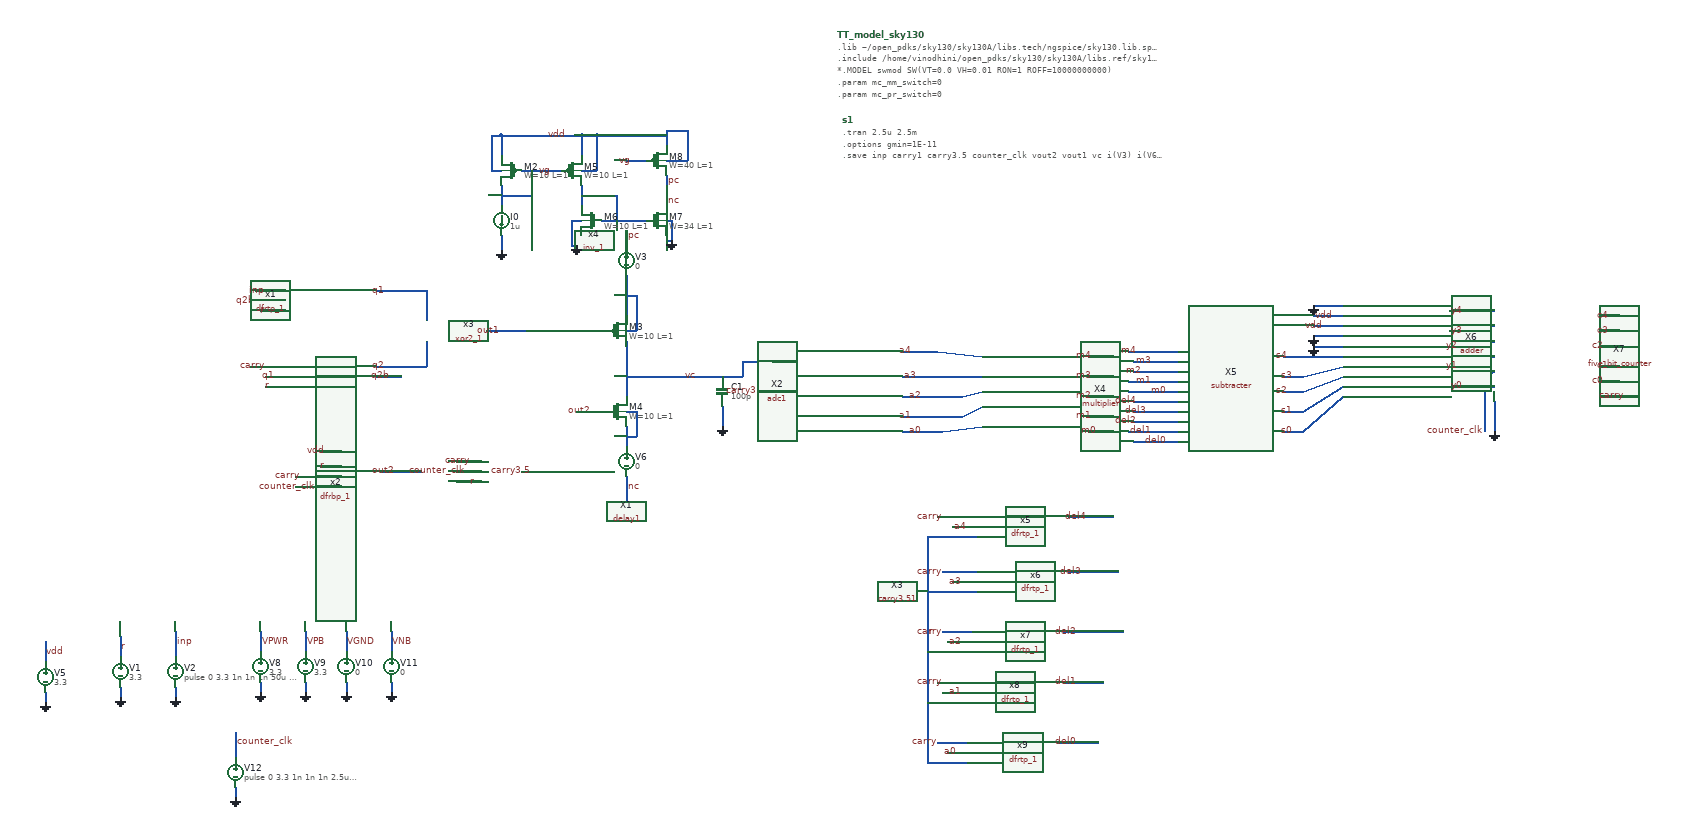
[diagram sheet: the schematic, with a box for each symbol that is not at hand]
v {xschem version=3.0.0 file_version=1.2 }
G {}
K {}
V {}
S {}
E {}
N -800 150 -800 170 { lab=GND}
N -800 40 -800 90 { lab=inp}
N -910 150 -910 170 { lab=GND}
N -910 50 -910 90 { lab=r}
N -1060 160 -1060 180 { lab=GND}
N -1060 60 -1060 100 { lab=vdd}
N 100 -370 100 -330 { lab=#net1}
N 100 -490 100 -430 { lab=vc}
N 100 -470 290 -470 { lab=vc}
N 100 -670 100 -600 { lab=#net2}
N 290 -410 290 -370 { lab=GND}
N 100 -540 100 -490 { lab=vc}
N 0 -560 10 -560 { lab=#net3}
N 50 -560 60 -560 { lab=#net3}
N 100 -610 100 -590 { lab=#net2}
N 0 -400 60 -400 { lab=out2}
N 100 -400 120 -400 { lab=#net1}
N 120 -400 120 -350 { lab=#net1}
N 100 -350 120 -350 { lab=#net1}
N 100 -560 120 -560 { lab=#net2}
N 120 -630 120 -560 { lab=#net2}
N 100 -630 120 -630 { lab=#net2}
N 360 -440 440 -440 { lab=carry3.5}
N 650 -360 730 -360 { lab=a0}
N 650 -390 720 -390 { lab=a1}
N 650 -430 720 -430 { lab=a2}
N 650 -470 730 -470 { lab=a3}
N 390 -500 440 -500 { lab=vc}
N 650 -520 720 -520 { lab=a4}
N 100 -760 100 -730 { lab=pc}
N 100 -270 100 -220 { lab=nc}
N -400 -470 -350 -470 { lab=q2b}
N -640 -620 -580 -620 { lab=q2b}
N -400 -490 -350 -490 { lab=q2}
N -400 -640 -350 -640 { lab=q1}
N -620 -450 -580 -450 { lab=r}
N -630 -600 -580 -600 { lab=r}
N -650 -490 -580 -490 { lab=carry}
N -640 -640 -580 -640 { lab=inp}
N -620 -470 -580 -470 { lab=q1}
N -350 -640 -310 -640 { lab=q1}
N -310 -640 -300 -640 { lab=q1}
N -300 -640 -300 -580 { lab=q1}
N -350 -490 -310 -490 { lab=q2}
N -310 -490 -300 -490 { lab=q2}
N -300 -540 -300 -490 { lab=q2}
N -180 -560 -100 -560 { lab=out1}
N -20 -560 10 -560 { lab=#net3}
N -0 -560 50 -560 { lab=#net3}
N 290 -470 330 -470 { lab=vc}
N -630 140 -630 160 { lab=GND}
N -630 40 -630 80 { lab=VPWR}
N -540 140 -540 160 { lab=GND}
N -540 40 -540 80 { lab=VPB}
N -460 140 -460 160 { lab=GND}
N -460 40 -460 80 { lab=VGND}
N -370 140 -370 160 { lab=GND}
N -370 40 -370 80 { lab=VNB}
N -560 -250 -470 -250 { lab=counter_clk}
N -560 -270 -470 -270 { lab=carry}
N -510 -290 -470 -290 { lab=r}
N -510 -320 -470 -320 { lab=vdd}
N -680 350 -680 370 { lab=GND}
N -680 240 -680 290 { lab=counter_clk}
N -390 -280 -310 -280 { lab=out2}
N -150 -950 -150 -910 { lab=vdd}
N -170 -880 -150 -880 { lab=vdd}
N -170 -950 -170 -880 { lab=vdd}
N -170 -950 -150 -950 { lab=vdd}
N -150 -850 -150 -810 { lab=vg}
N -150 -750 -150 -720 { lab=GND}
N -110 -880 -30 -880 { lab=vg}
N -150 -830 -90 -830 { lab=vg}
N -90 -880 -90 -830 { lab=vg}
N 10 -880 40 -880 { lab=vdd}
N 40 -950 40 -880 { lab=vdd}
N 10 -950 40 -950 { lab=vdd}
N 10 -950 10 -910 { lab=vdd}
N -150 -950 10 -950 { lab=vdd}
N 10 -850 10 -810 { lab=#net4}
N -10 -780 10 -780 { lab=GND}
N -10 -780 -10 -730 { lab=GND}
N -10 -730 10 -730 { lab=GND}
N 10 -750 10 -730 { lab=GND}
N 50 -780 140 -780 { lab=#net4}
N 180 -780 190 -780 { lab=GND}
N 190 -780 190 -740 { lab=GND}
N 180 -740 190 -740 { lab=GND}
N 180 -750 180 -740 { lab=GND}
N 10 -830 80 -830 { lab=#net4}
N 80 -830 80 -780 { lab=#net4}
N 180 -900 220 -900 { lab=vdd}
N 220 -960 220 -900 { lab=vdd}
N 180 -960 220 -960 { lab=vdd}
N 180 -960 180 -930 { lab=vdd}
N 40 -950 180 -950 { lab=vdd}
N 100 -900 140 -900 { lab=vg}
N 180 -870 180 -850 { lab=pc}
N 180 -830 180 -810 { lab=nc}
N -240 -300 -190 -300 { lab=carry}
N -240 -280 -190 -280 { lab=counter_clk}
N -240 -260 -190 -260 { lab=r}
N -110 -280 -60 -280 { lab=carry3.5}
N 720 -520 810 -510 { lab=a4}
N 730 -470 810 -470 { lab=a3}
N 720 -430 740 -430 { lab=a2}
N 740 -430 750 -430 { lab=a2}
N 750 -430 760 -430 { lab=a2}
N 760 -430 770 -430 { lab=a2}
N 770 -430 810 -440 { lab=a2}
N 720 -390 770 -390 { lab=a1}
N 770 -390 810 -410 { lab=a1}
N 730 -360 810 -370 { lab=a0}
N 720 -190 800 -190 { lab=carry}
N 750 -170 800 -170 { lab=a4}
N 700 -150 800 -150 { lab=r}
N 700 -150 700 300 { lab=r}
N 700 300 780 300 { lab=r}
N 700 180 790 180 { lab=r}
N 700 80 790 80 { lab=r}
N 700 -40 800 -40 { lab=r}
N 730 -80 800 -80 { lab=carry}
N 750 -60 800 -60 { lab=a3}
N 730 40 790 40 { lab=carry}
N 740 60 790 60 { lab=a2}
N 720 140 790 140 { lab=carry}
N 730 160 790 160 { lab=a1}
N 720 260 780 260 { lab=carry}
N 740 280 780 280 { lab=a0}
N 980 -190 1070 -190 { lab=del4}
N 980 -80 1080 -80 { lab=del3}
N 970 40 1090 40 { lab=del2}
N 970 140 1050 140 { lab=del1}
N 960 260 1040 260 { lab=del0}
N 1020 -360 1070 -360 { lab=m0}
N 1020 -390 1070 -390 { lab=m1}
N 1020 -430 1070 -430 { lab=m2}
N 1020 -470 1070 -470 { lab=m3}
N 1020 -510 1070 -510 { lab=m4}
N 1110 -340 1200 -340 { lab=del0}
N 1100 -360 1200 -360 { lab=del1}
N 1110 -380 1200 -380 { lab=del2}
N 1110 -400 1200 -400 { lab=del3}
N 1110 -420 1200 -420 { lab=del4}
N 1100 -440 1200 -440 { lab=m0}
N 1100 -460 1200 -460 { lab=m1}
N 1110 -480 1200 -480 { lab=m2}
N 1110 -500 1200 -500 { lab=m3}
N 1100 -520 1200 -520 { lab=m4}
N 1410 -360 1450 -360 { lab=s0}
N 1410 -400 1450 -400 { lab=s1}
N 1410 -440 1450 -440 { lab=s2}
N 1410 -470 1450 -470 { lab=s3}
N 1410 -510 1450 -510 { lab=s4}
N 1450 -510 1530 -510 { lab=s4}
N 1450 -470 1530 -490 { lab=s3}
N 1450 -440 1530 -470 { lab=s2}
N 1450 -400 1530 -450 { lab=s1}
N 1450 -360 1530 -430 { lab=s0}
N 1470 -610 1530 -610 { lab=GND}
N 1470 -590 1530 -590 { lab=vdd}
N 1470 -570 1530 -570 { lab=vdd}
N 1470 -550 1530 -550 { lab=GND}
N 1470 -530 1530 -530 { lab=GND}
N 1740 -450 1780 -450 { lab=y0}
N 1740 -490 1780 -490 { lab=y1}
N 1740 -530 1780 -530 { lab=y2}
N 1740 -560 1780 -560 { lab=y3}
N 1740 -600 1780 -600 { lab=y4}
N 1780 -600 1830 -600 { lab=y4}
N 1780 -560 1830 -570 { lab=y3}
N 1780 -530 1830 -540 { lab=y2}
N 1780 -490 1830 -510 { lab=y1}
N 1780 -450 1830 -480 { lab=y0}
N 1810 -450 1830 -450 { lab=counter_clk}
N 1810 -450 1810 -360 { lab=counter_clk}
N 1830 -420 1830 -360 { lab=GND}
N 2040 -430 2120 -430 { lab=carry}
N 2040 -460 2080 -460 { lab=c0}
N 2040 -490 2080 -490 { lab=c1}
N 2040 -530 2070 -530 { lab=c2}
N 2070 -530 2080 -530 { lab=c2}
N 2040 -560 2080 -560 { lab=c3}
N 2040 -590 2080 -590 { lab=c4}
N 330 -500 330 -470 { lab=vc}
N 330 -500 400 -500 { lab=vc}
C {devices/code.sym} 520 -1150 0 0 {name=TT_model_sky130
format=@value
only_toplevel=true
value="
.lib ~/open_pdks/sky130/sky130A/libs.tech/ngspice/sky130.lib.spice tt
.include /home/vinodhini/open_pdks/sky130/sky130A/libs.ref/sky130_fd_sc_hvl/spice/sky130_fd_sc_hvl.spice

*.MODEL swmod SW(VT=0.0 VH=0.01 RON=1 ROFF=10000000000)
.param mc_mm_switch=0
.param mc_pr_switch=0"

.include ~/open_pdks/sky130/sky130A/libs.tech/ngspice/corners/tt/nonfet.spice


*model
*.include ~/open_pdks/sky130/sky130A/libs.tech/ngspice/all.spice


 
*mosfet
*.include ~/open_pdks/sky130/sky130A/libs.ref/sky130_fd_pr/spice/sky130_fd_pr__pfet_g5v0d10v5__tt.corner.spice
*.inclued ~/open_pdks/sky130/sky130A/libs.ref/sky130_fd_pr/spice/sky130_fd_pr__nfet_g5v0d10v5__tt.corner.spice
*mismatch parameters
*.include ~/open_pdks/sky130/sky130A/libs.ref/sky130_fd_pr/spice/sky130_fd_pr__pfet_g5v0d10v5__mismatch.corner.spice
*.include ~/open_pdks/sky130/sky130A/libs.ref/sky130_fd_pr/spice/sky130_fd_pr__nfet_g5v0d10v5__mismatch.corner.spice
}
C {devices/code_shown.sym} 530 -980 0 0 {name=s1 only_toplevel=false value="
.tran 2.5u 2.5m
.options gmin=1E-11
.save inp carry1 carry3.5 counter_clk vout2 vout1 vc i(V3) i(V6) a0 a1 a2 a3 a4 m0 m1 m2 m3 m4 del0 del1 del2 del3 del4 s0 s1 s2 s3 s4"}
C {devices/vsource.sym} -800 120 0 0 {name=V2 value="pulse 0 3.3 1n 1n 1n 50u 100u"}
C {devices/gnd.sym} -800 170 0 0 {name=l22 lab=GND}
C {devices/lab_pin.sym} -800 60 2 0 {name=l25 sig_type=std_logic lab=inp}
C {devices/vsource.sym} -910 120 0 0 {name=V1 value=3.3}
C {devices/gnd.sym} -910 170 0 0 {name=l4 lab=GND}
C {devices/lab_pin.sym} -910 70 2 0 {name=l5 sig_type=std_logic lab=r}
C {devices/vsource.sym} -1060 130 0 0 {name=V5 value=3.3}
C {devices/gnd.sym} -1060 180 0 0 {name=l26 lab=GND}
C {devices/lab_pin.sym} -1060 80 2 0 {name=l27 sig_type=std_logic lab=vdd}
C {devices/gnd.sym} 290 -370 0 0 {name=l32 lab=GND}
C {devices/capa.sym} 290 -440 0 0 {name=C1
m=1
value=100p
footprint=1206
device="ceramic capacitor"}
C {devices/lab_pin.sym} 240 -470 1 0 {name=l33 sig_type=std_logic lab=vc}
C {sky130_fd_pr/pfet_g5v0d10v5.sym} 80 -560 0 0 {name=M3
L=1
W=10
nf=1
mult=1
ad="'int((nf+1)/2) * W/nf * 0.29'" 
pd="'2*int((nf+1)/2) * (W/nf + 0.29)'"
as="'int((nf+2)/2) * W/nf * 0.29'" 
ps="'2*int((nf+2)/2) * (W/nf + 0.29)'"
nrd="'0.29 / W'" nrs="'0.29 / W'"
sa=0 sb=0 sd=0
model=pfet_g5v0d10v5
spiceprefix=X
}
C {sky130_fd_pr/nfet_g5v0d10v5.sym} 80 -400 0 0 {name=M4
L=1
W=10
nf=1
mult=1
ad="'int((nf+1)/2) * W/nf * 0.29'" 
pd="'2*int((nf+1)/2) * (W/nf + 0.29)'"
as="'int((nf+2)/2) * W/nf * 0.29'" 
ps="'2*int((nf+2)/2) * (W/nf + 0.29)'"
nrd="'0.29 / W'" nrs="'0.29 / W'"
sa=0 sb=0 sd=0
model=nfet_g5v0d10v5
spiceprefix=X
}
C {devices/lab_pin.sym} 30 -400 1 0 {name=l30 sig_type=std_logic lab=out2}
C {devices/lab_pin.sym} 380 -440 3 0 {name=l36 sig_type=std_logic lab=carry3.5}
C {devices/lab_pin.sym} 690 -360 3 0 {name=l37 sig_type=std_logic lab=a0}
C {devices/lab_pin.sym} 670 -390 3 0 {name=l38 sig_type=std_logic lab=a1}
C {devices/lab_pin.sym} 690 -430 3 0 {name=l39 sig_type=std_logic lab=a2}
C {devices/lab_pin.sym} 680 -470 3 0 {name=l40 sig_type=std_logic lab=a3}
C {devices/lab_pin.sym} 670 -520 3 0 {name=l64 sig_type=std_logic lab=a4}
C {devices/vsource.sym} 100 -700 0 0 {name=V3 value=0}
C {devices/vsource.sym} 100 -300 0 0 {name=V6 value=0}
C {sky130_stdcells/dfrbp_1.sym} -490 -470 0 0 {name=x2 VGND=VGND VNB=VNB VPB=VPB VPWR=VPWR prefix=sky130_fd_sc_hvl__ }
C {devices/lab_pin.sym} -370 -470 3 0 {name=l35 sig_type=std_logic lab=q2b}
C {devices/lab_pin.sym} -640 -620 0 0 {name=l97 sig_type=std_logic lab=q2b}
C {devices/lab_pin.sym} -380 -490 1 0 {name=l98 sig_type=std_logic lab=q2}
C {sky130_stdcells/dfrtp_1.sym} -490 -620 0 0 {name=x1 VGND=VGND VNB=VNB VPB=VPB VPWR=VPWR prefix=sky130_fd_sc_hvl__ }
C {devices/lab_pin.sym} -380 -640 1 0 {name=l99 sig_type=std_logic lab=q1}
C {devices/lab_pin.sym} -610 -450 1 0 {name=l100 sig_type=std_logic lab=r}
C {devices/lab_pin.sym} -620 -600 1 0 {name=l101 sig_type=std_logic lab=r}
C {devices/lab_pin.sym} -620 -490 1 0 {name=l102 sig_type=std_logic lab=carry}
C {devices/lab_pin.sym} -620 -640 1 0 {name=l103 sig_type=std_logic lab=inp}
C {devices/lab_pin.sym} -600 -470 1 0 {name=l104 sig_type=std_logic lab=q1}
C {sky130_stdcells/xor2_1.sym} -240 -560 0 0 {name=x3 VGND=VGND VNB=VNB VPB=VPB VPWR=VPWR prefix=sky130_fd_sc_hvl__ }
C {devices/lab_pin.sym} -150 -560 1 0 {name=l1 sig_type=std_logic lab=out1}
C {sky130_stdcells/inv_1.sym} -60 -560 0 0 {name=x4 VGND=VGND VNB=VNB VPB=VPB VPWR=VPWR prefix=sky130_fd_sc_hvl__ }
C {devices/vsource.sym} -630 110 0 0 {name=V8 value=3.3}
C {devices/gnd.sym} -630 160 0 0 {name=l6 lab=GND}
C {devices/lab_pin.sym} -630 60 2 0 {name=l7 sig_type=std_logic lab=VPWR}
C {devices/vsource.sym} -540 110 0 0 {name=V9 value=3.3}
C {devices/gnd.sym} -540 160 0 0 {name=l8 lab=GND}
C {devices/lab_pin.sym} -540 60 2 0 {name=l9 sig_type=std_logic lab=VPB}
C {devices/vsource.sym} -460 110 0 0 {name=V10 value=0}
C {devices/gnd.sym} -460 160 0 0 {name=l10 lab=GND}
C {devices/lab_pin.sym} -460 60 2 0 {name=l11 sig_type=std_logic lab=VGND}
C {devices/vsource.sym} -370 110 0 0 {name=V11 value=0}
C {devices/gnd.sym} -370 160 0 0 {name=l12 lab=GND}
C {devices/lab_pin.sym} -370 60 2 0 {name=l13 sig_type=std_logic lab=VNB}
C {/home/vinodhini/Documents/delay1.sym} 270 -20 0 0 {name=X1}
C {devices/lab_pin.sym} -550 -270 1 0 {name=l14 sig_type=std_logic lab=carry}
C {devices/lab_pin.sym} -500 -290 1 0 {name=l15 sig_type=std_logic lab=r}
C {devices/lab_pin.sym} -500 -320 1 0 {name=l16 sig_type=std_logic lab=vdd}
C {devices/lab_pin.sym} -520 -250 3 0 {name=l19 sig_type=std_logic lab=counter_clk}
C {devices/vsource.sym} -680 320 0 0 {name=V12 value="pulse 0 3.3 1n 1n 1n 2.5u 5u"}
C {devices/gnd.sym} -680 370 0 0 {name=l20 lab=GND}
C {devices/lab_pin.sym} -680 260 2 0 {name=l23 sig_type=std_logic lab=counter_clk}
C {devices/lab_pin.sym} -360 -280 1 0 {name=l24 sig_type=std_logic lab=out2}
C {sky130_fd_pr/pfet_g5v0d10v5.sym} -130 -880 0 1 {name=M2
L=1
W=10
nf=1
mult=1
ad="'int((nf+1)/2) * W/nf * 0.29'" 
pd="'2*int((nf+1)/2) * (W/nf + 0.29)'"
as="'int((nf+2)/2) * W/nf * 0.29'" 
ps="'2*int((nf+2)/2) * (W/nf + 0.29)'"
nrd="'0.29 / W'" nrs="'0.29 / W'"
sa=0 sb=0 sd=0
model=pfet_g5v0d10v5
spiceprefix=X
}
C {devices/isource.sym} -150 -780 0 0 {name=I0 value=1u}
C {devices/gnd.sym} -150 -720 0 0 {name=l21 lab=GND}
C {sky130_fd_pr/pfet_g5v0d10v5.sym} -10 -880 0 0 {name=M5
L=1
W=10
nf=1
mult=1
ad="'int((nf+1)/2) * W/nf * 0.29'" 
pd="'2*int((nf+1)/2) * (W/nf + 0.29)'"
as="'int((nf+2)/2) * W/nf * 0.29'" 
ps="'2*int((nf+2)/2) * (W/nf + 0.29)'"
nrd="'0.29 / W'" nrs="'0.29 / W'"
sa=0 sb=0 sd=0
model=pfet_g5v0d10v5
spiceprefix=X
}
C {sky130_fd_pr/nfet_g5v0d10v5.sym} 30 -780 0 1 {name=M6
L=1
W=10
nf=1
mult=1
ad="'int((nf+1)/2) * W/nf * 0.29'" 
pd="'2*int((nf+1)/2) * (W/nf + 0.29)'"
as="'int((nf+2)/2) * W/nf * 0.29'" 
ps="'2*int((nf+2)/2) * (W/nf + 0.29)'"
nrd="'0.29 / W'" nrs="'0.29 / W'"
sa=0 sb=0 sd=0
model=nfet_g5v0d10v5
spiceprefix=X
}
C {devices/gnd.sym} 0 -730 0 0 {name=l31 lab=GND}
C {sky130_fd_pr/nfet_g5v0d10v5.sym} 160 -780 0 0 {name=M7
L=1
W=34
nf=1
mult=1
ad="'int((nf+1)/2) * W/nf * 0.29'" 
pd="'2*int((nf+1)/2) * (W/nf + 0.29)'"
as="'int((nf+2)/2) * W/nf * 0.29'" 
ps="'2*int((nf+2)/2) * (W/nf + 0.29)'"
nrd="'0.29 / W'" nrs="'0.29 / W'"
sa=0 sb=0 sd=0
model=nfet_g5v0d10v5
spiceprefix=X
}
C {devices/gnd.sym} 190 -740 0 0 {name=l34 lab=GND}
C {sky130_fd_pr/pfet_g5v0d10v5.sym} 160 -900 0 0 {name=M8
L=1
W=40
nf=1
mult=1
ad="'int((nf+1)/2) * W/nf * 0.29'" 
pd="'2*int((nf+1)/2) * (W/nf + 0.29)'"
as="'int((nf+2)/2) * W/nf * 0.29'" 
ps="'2*int((nf+2)/2) * (W/nf + 0.29)'"
nrd="'0.29 / W'" nrs="'0.29 / W'"
sa=0 sb=0 sd=0
model=pfet_g5v0d10v5
spiceprefix=X
}
C {devices/lab_pin.sym} -50 -880 1 0 {name=l42 sig_type=std_logic lab=vg}
C {devices/lab_pin.sym} 110 -900 1 0 {name=l43 sig_type=std_logic lab=vg}
C {devices/lab_pin.sym} 180 -860 2 0 {name=l28 sig_type=std_logic lab=pc}
C {devices/lab_pin.sym} 180 -820 2 0 {name=l29 sig_type=std_logic lab=nc}
C {devices/lab_pin.sym} 100 -750 2 0 {name=l44 sig_type=std_logic lab=pc}
C {devices/lab_pin.sym} 100 -250 2 0 {name=l45 sig_type=std_logic lab=nc}
C {devices/lab_pin.sym} -20 -950 1 0 {name=l46 sig_type=std_logic lab=vdd}
C {/home/vinodhini/Documents/adc1.sym} 600 -390 0 0 {name=X2}
C {/home/vinodhini/Documents/carry3.51.sym} 550 -30 0 0 {name=X3}
C {devices/lab_pin.sym} -200 -260 3 0 {name=l41 sig_type=std_logic lab=r}
C {devices/lab_pin.sym} -220 -280 3 0 {name=l47 sig_type=std_logic lab=counter_clk}
C {devices/lab_pin.sym} -210 -300 1 0 {name=l48 sig_type=std_logic lab=carry}
C {devices/lab_pin.sym} -90 -280 1 0 {name=l49 sig_type=std_logic lab=carry3.5}
C {/home/vinodhini/Documents/multiplier.sym} 970 -390 0 0 {name=X4}
C {sky130_stdcells/dfrtp_1.sym} 890 -170 0 0 {name=x5 VGND=VGND VNB=VNB VPB=VPB VPWR=VPWR prefix=sky130_fd_sc_hvl__ }
C {sky130_stdcells/dfrtp_1.sym} 890 -60 0 0 {name=x6 VGND=VGND VNB=VNB VPB=VPB VPWR=VPWR prefix=sky130_fd_sc_hvl__ }
C {sky130_stdcells/dfrtp_1.sym} 880 60 0 0 {name=x7 VGND=VGND VNB=VNB VPB=VPB VPWR=VPWR prefix=sky130_fd_sc_hvl__ }
C {sky130_stdcells/dfrtp_1.sym} 880 160 0 0 {name=x8 VGND=VGND VNB=VNB VPB=VPB VPWR=VPWR prefix=sky130_fd_sc_hvl__ }
C {sky130_stdcells/dfrtp_1.sym} 870 280 0 0 {name=x9 VGND=VGND VNB=VNB VPB=VPB VPWR=VPWR prefix=sky130_fd_sc_hvl__ }
C {devices/lab_pin.sym} 700 40 2 0 {name=l2 sig_type=std_logic lab=r}
C {devices/lab_pin.sym} 730 -190 1 0 {name=l3 sig_type=std_logic lab=carry}
C {devices/lab_pin.sym} 730 -80 1 0 {name=l50 sig_type=std_logic lab=carry}
C {devices/lab_pin.sym} 730 40 1 0 {name=l51 sig_type=std_logic lab=carry}
C {devices/lab_pin.sym} 730 140 1 0 {name=l52 sig_type=std_logic lab=carry}
C {devices/lab_pin.sym} 720 260 1 0 {name=l53 sig_type=std_logic lab=carry}
C {devices/lab_pin.sym} 760 280 1 0 {name=l54 sig_type=std_logic lab=a0}
C {devices/lab_pin.sym} 770 160 1 0 {name=l55 sig_type=std_logic lab=a1}
C {devices/lab_pin.sym} 770 60 1 0 {name=l56 sig_type=std_logic lab=a2}
C {devices/lab_pin.sym} 770 -60 1 0 {name=l57 sig_type=std_logic lab=a3}
C {devices/lab_pin.sym} 780 -170 1 0 {name=l58 sig_type=std_logic lab=a4}
C {devices/lab_pin.sym} 1000 260 1 0 {name=l59 sig_type=std_logic lab=del0}
C {devices/lab_pin.sym} 1000 140 1 0 {name=l60 sig_type=std_logic lab=del1}
C {devices/lab_pin.sym} 1000 40 1 0 {name=l61 sig_type=std_logic lab=del2}
C {devices/lab_pin.sym} 1010 -80 1 0 {name=l62 sig_type=std_logic lab=del3}
C {devices/lab_pin.sym} 1020 -190 1 0 {name=l63 sig_type=std_logic lab=del4}
C {/home/vinodhini/Documents/subtracter.sym} 1360 -370 0 0 {name=X5}
C {devices/lab_pin.sym} 1040 -360 3 0 {name=l65 sig_type=std_logic lab=m0}
C {devices/lab_pin.sym} 1030 -390 3 0 {name=l66 sig_type=std_logic lab=m1}
C {devices/lab_pin.sym} 1030 -430 3 0 {name=l67 sig_type=std_logic lab=m2}
C {devices/lab_pin.sym} 1030 -470 3 0 {name=l68 sig_type=std_logic lab=m3}
C {devices/lab_pin.sym} 1030 -510 3 0 {name=l69 sig_type=std_logic lab=m4}
C {devices/lab_pin.sym} 1180 -440 3 0 {name=l70 sig_type=std_logic lab=m0}
C {devices/lab_pin.sym} 1150 -460 3 0 {name=l71 sig_type=std_logic lab=m1}
C {devices/lab_pin.sym} 1130 -480 3 0 {name=l72 sig_type=std_logic lab=m2}
C {devices/lab_pin.sym} 1150 -500 3 0 {name=l73 sig_type=std_logic lab=m3}
C {devices/lab_pin.sym} 1120 -520 3 0 {name=l74 sig_type=std_logic lab=m4}
C {devices/lab_pin.sym} 1120 -420 1 0 {name=l75 sig_type=std_logic lab=del4}
C {devices/lab_pin.sym} 1140 -400 1 0 {name=l76 sig_type=std_logic lab=del3}
C {devices/lab_pin.sym} 1120 -380 3 0 {name=l77 sig_type=std_logic lab=del2}
C {devices/lab_pin.sym} 1150 -360 3 0 {name=l78 sig_type=std_logic lab=del1}
C {devices/lab_pin.sym} 1180 -340 3 0 {name=l79 sig_type=std_logic lab=del0}
C {devices/lab_pin.sym} 1430 -360 3 0 {name=l80 sig_type=std_logic lab=s0}
C {devices/lab_pin.sym} 1430 -400 3 0 {name=l81 sig_type=std_logic lab=s1}
C {devices/lab_pin.sym} 1420 -440 3 0 {name=l82 sig_type=std_logic lab=s2}
C {devices/lab_pin.sym} 1430 -470 3 0 {name=l83 sig_type=std_logic lab=s3}
C {devices/lab_pin.sym} 1420 -510 3 0 {name=l84 sig_type=std_logic lab=s4}
C {/home/vinodhini/Documents/adder.sym} 1690 -460 0 0 {name=X6}
C {devices/gnd.sym} 1470 -530 0 0 {name=l85 lab=GND}
C {devices/gnd.sym} 1470 -550 0 0 {name=l86 lab=GND}
C {devices/gnd.sym} 1470 -610 0 0 {name=l87 lab=GND}
C {devices/lab_pin.sym} 1510 -590 3 0 {name=l88 sig_type=std_logic lab=vdd}
C {devices/lab_pin.sym} 1490 -570 3 0 {name=l89 sig_type=std_logic lab=vdd}
C {/home/vinodhini/Documents/five_bit_counter.sym} 1990 -450 0 0 {name=X7}
C {devices/lab_pin.sym} 1810 -360 3 0 {name=l90 sig_type=std_logic lab=counter_clk}
C {devices/lab_pin.sym} 2090 -430 3 0 {name=l91 sig_type=std_logic lab=carry}
C {devices/gnd.sym} 1830 -360 0 0 {name=l92 lab=GND}
C {devices/lab_pin.sym} 2050 -460 3 0 {name=l93 sig_type=std_logic lab=c0}
C {devices/lab_pin.sym} 2060 -490 3 0 {name=l94 sig_type=std_logic lab=c1}
C {devices/lab_pin.sym} 2050 -530 3 0 {name=l95 sig_type=std_logic lab=c2}
C {devices/lab_pin.sym} 2060 -560 3 0 {name=l96 sig_type=std_logic lab=c3}
C {devices/lab_pin.sym} 2060 -590 3 0 {name=l105 sig_type=std_logic lab=c4}
C {devices/lab_pin.sym} 1770 -450 3 0 {name=l17 sig_type=std_logic lab=y0}
C {devices/lab_pin.sym} 1760 -490 3 0 {name=l18 sig_type=std_logic lab=y1}
C {devices/lab_pin.sym} 1760 -530 3 0 {name=l106 sig_type=std_logic lab=y2}
C {devices/lab_pin.sym} 1770 -560 3 0 {name=l107 sig_type=std_logic lab=y3}
C {devices/lab_pin.sym} 1770 -600 3 0 {name=l108 sig_type=std_logic lab=y4}
